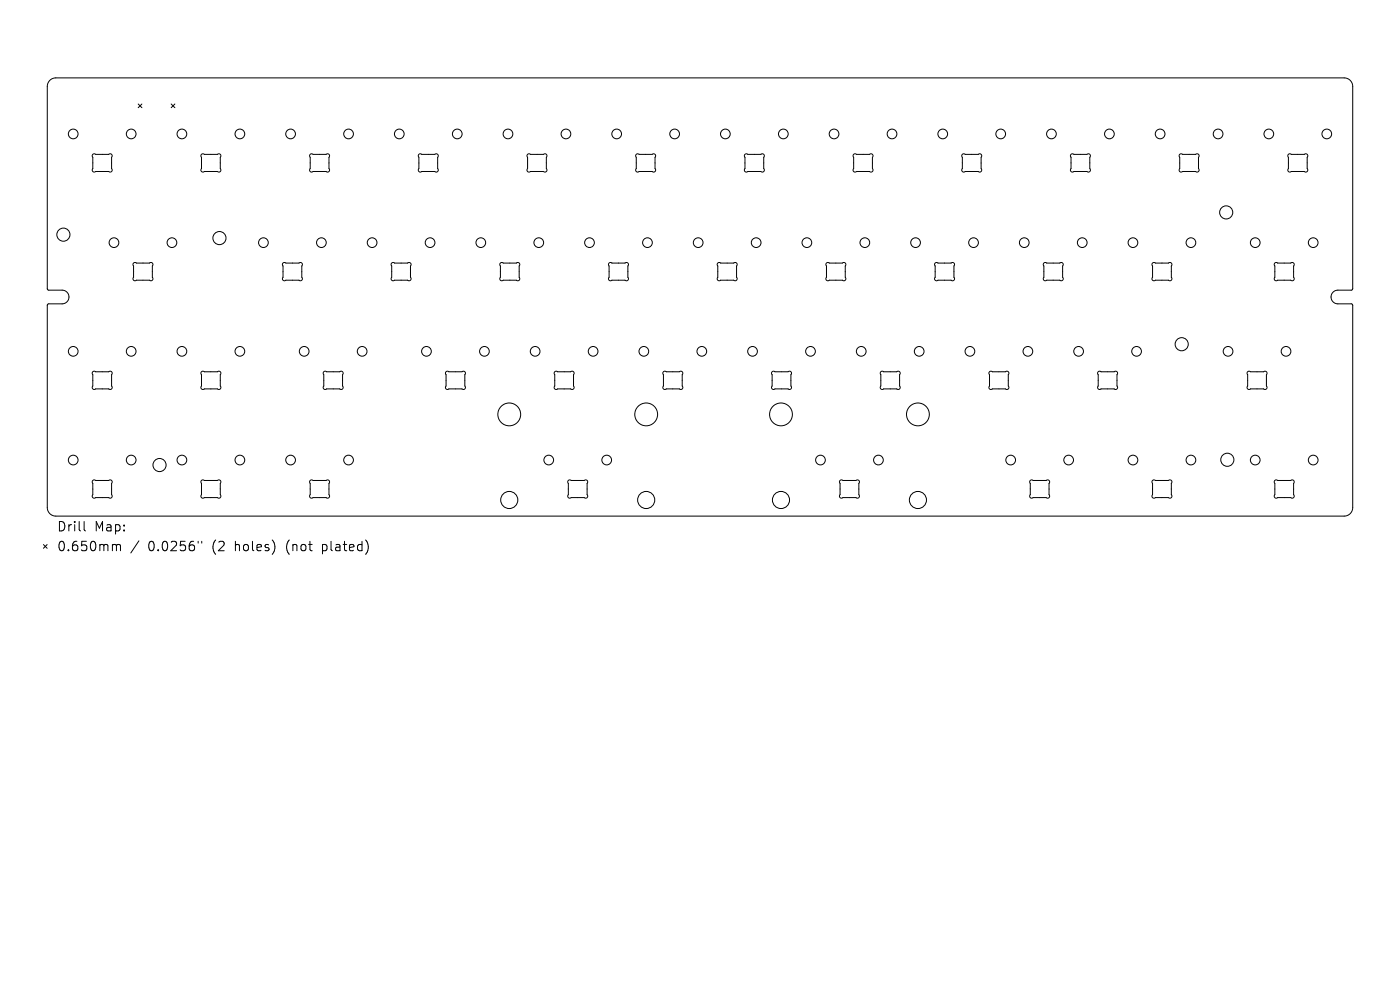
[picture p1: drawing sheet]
<svg xmlns="http://www.w3.org/2000/svg" width="297mm" height="210mm" viewBox="0 0 297 210" stroke-linecap="round" stroke-linejoin="round" font-family="sans-serif">
<defs><g id="words">
<g font-size="2.8">
<text x="12" y="113">Drill</text>
<text x="20" y="113">Map:</text>
<text x="12" y="117.2">0.650mm</text>
<text x="31.4" y="117.2">0.0256&quot;</text>
<text x="45.2" y="117.2">(2</text>
<text x="50.1" y="117.2">holes)</text>
<text x="61.2" y="117.2">(not</text>
<text x="69" y="117.2">plated)</text>
</g>
</g></defs>
<g fill="none" stroke="#000" stroke-width=".21">
<path d="M10.6 17.1l.6-.5 .6-.1h273.4a1.81 1.81 0 0 1 1.8 1.8v43l-.3 .2h-2.9a1.45 1.45 0 0 0-1.4 1.5 1.45 1.45 0 0 0 1.4 1.5h2.9l.3 .2v43a1.81 1.81 0 0 1-1.8 1.8h-273.4a1.82 1.82 0 0 1-1.8-1.8v-43l.3-.2h2.9a1.45 1.45 0 0 0 1.4-1.5 1.45 1.45 0 0 0-1.4-1.5h-2.9l-.3-.2v-43l.2-.7zM19.7 32.7l.3-.1 .3 .1h2.8l.3-.1 .3 .1 .1 .4-.1 .3v3l-.3 .1-.3-.1h-2.8l-.3 .1-.3-.1-.1-.3 .1-.3v-2.4l-.1-.3zM29.3 22.1l.8 .7M30.1 22.1l-.8 .7M36.3 22.1l.8 .7M37.1 22.1l-.8 .7M42.7 32.7l.3-.1 .3 .1h2.8l.3-.1 .3 .1 .2 .4-.2 .3 .1 3-.4 .1-.3-.1h-2.8l-.3 .1-.2-.1-.2-.3 .1-.3v-2.4l-.1-.3zM65.8 32.7l.3-.1 .3 .1h2.8l.3-.1 .3 .1 .1 .4-.1 .3v3l-.3 .1-.3-.1h-2.8l-.3 .1-.3-.1-.1-.3 .1-.3v-2.4l-.1-.3zM88.9 32.7l.3-.1 .3 .1h2.7l.4-.1 .2 .1 .2 .4-.2 .3 .1 3-.4 .1-.3-.1h-2.7l-.3 .1-.3-.1-.2-.3 .2-.3v-2.4l-.2-.3zM111.9 32.7l.3-.1 .3 .1h2.8l.3-.1 .3 .1 .1 .4-.1 .3v3l-.3 .1-.3-.1h-2.8l-.3 .1-.3-.1-.1-.3 .1-.3v-2.4l-.1-.3zM135 32.7l.3-.1 .3 .1h2.8l.3-.1 .2 .1 .2 .4-.1 .3v3l-.3 .1-.3-.1h-2.8l-.3 .1-.3-.1-.2-.3 .2-.3v-2.4l-.2-.3zM158 32.7l.3-.1 .3 .1h2.8l.3-.1 .3 .1 .2 .4-.2 .3 .1 3-.4 .1-.3-.1h-2.8l-.3 .1-.2-.1-.2-.3 .1-.3v-2.4l-.1-.3z"/>
<path d="M181.1 32.7l.3-.1 .3 .1h2.8l.3-.1 .3 .1 .1 .4-.1 .3v3l-.3 .1-.3-.1h-2.8l-.3 .1-.3-.1-.1-.3 .1-.3v-2.4l-.1-.3zM204.1 32.7l.4-.1 .3 .1h2.7l.3-.1 .3 .1 .2 .4-.2 .3 .1 3-.4 .1-.3-.1h-2.7l-.4 .1-.2-.1-.2-.3 .2-.3v-2.4l-.2-.3zM227.2 32.7l.3-.1 .3 .1h2.8l.3-.1 .3 .1 .1 .4-.1 .3v3l-.3 .1-.3-.1h-2.8l-.3 .1-.3-.1-.1-.3 .1-.3v-2.4l-.1-.3zM250.3 32.7l.3-.1 .3 .1h2.8l.3-.1 .2 .1 .2 .3-.1 .4v3l-.3 .1-.3-.1h-2.8l-.3 .1-.3-.1-.2-.3 .2-.3v-2.4l-.2-.3zM273.3 32.7l.3-.1 .3 .1h2.8l.3-.1 .3 .1 .1 .3-.1 .4v3l-.3 .1-.3-.1h-2.8l-.3 .1-.3-.1-.1-.3 .1-.3v-2.4l-.1-.3zM28.3 55.8l.3-.1 .3 .1h2.8l.3-.1 .3 .1 .1 .3-.1 .3v3l-.3 .2-.3-.2h-2.8l-.3 .2-.2-.1-.2-.4 .1-.3v-2.4l-.1-.3zM60 55.8l.3-.1 .3 .1h2.8l.3-.1 .3 .1 .2 .3-.2 .3 .1 3-.4 .2-.3-.2h-2.8l-.3 .2-.2-.1-.2-.4 .1-.3v-2.4l-.1-.3zM83.1 55.8l.3-.1 .3 .1h2.8l.3-.1 .3 .1 .1 .3-.1 .3v3l-.3 .2-.3-.2h-2.8l-.3 .2-.3-.1-.1-.4 .1-.3v-2.4l-.1-.3zM106.2 55.8l.3-.1 .3 .1h2.7l.4-.1 .2 .1 .2 .3-.2 .3 .1 3-.4 .2-.3-.2h-2.7l-.4 .2-.2-.1-.2-.4 .2-.3v-2.4l-.2-.3zM129.2 55.8l.3-.1 .3 .1h2.8l.3-.1 .3 .1 .1 .3-.1 .3v3l-.3 .2-.3-.2h-2.8l-.3 .2-.3-.1-.1-.4 .1-.3v-2.4l-.1-.3zM152.3 55.8l.3-.1 .3 .1h2.8l.3-.1 .2 .1 .2 .3-.1 .3v3l-.3 .2-.3-.2h-2.8l-.3 .2-.3-.1-.2-.4 .2-.3v-2.4l-.2-.3zM175.3 55.8l.3-.1 .3 .1h2.8l.3-.1 .3 .1 .1 .3-.1 .3v3l-.3 .2-.3-.2h-2.8l-.3 .2-.3-.1-.1-.4 .1-.3v-2.4l-.1-.3z"/>
<path d="M198.4 55.8l.3-.1 .3 .1h2.8l.3-.1 .3 .1 .1 .3-.1 .3v3l-.3 .2-.3-.2h-2.8l-.3 .2-.3-.1-.1-.4 .1-.3v-2.4l-.1-.3zM221.4 55.8l.3-.1 .3 .1h2.8l.3-.1 .3 .1 .2 .3-.2 .3 .1 3-.4 .2-.3-.2h-2.8l-.3 .2-.2-.1-.2-.4 .1-.3v-2.4l-.1-.3zM244.5 55.8l.3-.1 .3 .1h2.8l.3-.1 .3 .1 .1 .3-.1 .3v3l-.3 .2-.3-.2h-2.8l-.3 .2-.3-.1-.1-.4 .1-.3v-2.4l-.1-.3zM270.4 55.8l.3-.1 .3 .1h2.8l.3-.1 .3 .1 .2 .3-.2 .3 .1 3-.4 .2-.3-.2h-2.8l-.3 .2-.2-.1-.2-.3 .1-.4v-2.4l-.1-.3zM19.7 78.9l.3-.2 .3 .2h2.8l.3-.2 .3 .1 .1 .4-.1 .3v3l-.3 .1-.3-.1h-2.8l-.3 .1-.3-.1-.1-.3 .1-.3v-2.4l-.1-.3zM42.7 78.9l.3-.2 .3 .2h2.8l.3-.2 .3 .1 .2 .4-.2 .3 .1 3-.4 .1-.3-.1h-2.8l-.3 .1-.2-.1-.2-.3 .1-.3v-2.4l-.1-.3zM68.7 78.9l.3-.2 .3 .2h2.8l.3-.2 .3 .1 .1 .4-.1 .3v3l-.3 .1-.3-.1h-2.8l-.3 .1-.3-.1-.1-.3 .1-.3v-2.4l-.1-.3zM94.6 78.9l.3-.2 .3 .2h2.8l.3-.2 .3 .1 .1 .4-.1 .3v3l-.3 .1-.3-.1h-2.8l-.3 .1-.3-.1-.1-.3 .1-.3v-2.4l-.1-.3zM117.7 78.9l.3-.2 .3 .2h2.8l.3-.2 .3 .1 .1 .4-.1 .3v3l-.3 .1-.3-.1h-2.8l-.3 .1-.3-.1-.1-.3 .1-.3v-2.4l-.1-.3zM140.7 78.9l.3-.2 .3 .2h2.8l.3-.2 .3 .1 .2 .4-.2 .3 .1 3-.4 .1-.3-.1h-2.8l-.3 .1-.2-.1-.2-.3 .1-.3v-2.4l-.1-.3zM163.8 78.9l.3-.2 .3 .2h2.8l.3-.2 .3 .1 .1 .4-.1 .3v3l-.3 .1-.3-.1h-2.8l-.3 .1-.3-.1-.1-.3 .1-.3v-2.4l-.1-.3zM186.9 78.9l.3-.2 .3 .2h2.7l.4-.2 .2 .1 .2 .4-.2 .3 .1 3-.4 .1-.3-.1h-2.7l-.3 .1-.3-.1-.2-.3 .2-.3v-2.4l-.2-.3z"/>
<path d="M209.9 78.9l.3-.2 .3 .2h2.8l.3-.2 .3 .1 .1 .4-.1 .3v3l-.3 .1-.3-.1h-2.8l-.3 .1-.3-.1-.1-.3 .1-.3v-2.4l-.1-.3zM233 78.9l.3-.2 .3 .2h2.8l.3-.2 .2 .1 .2 .4-.1 .3v3l-.3 .1-.3-.1h-2.8l-.3 .1-.3-.1-.2-.3 .2-.3v-2.4l-.2-.3zM264.7 78.9l.3-.2 .3 .2h2.8l.3-.2 .3 .1 .1 .4-.1 .3v3l-.3 .1-.3-.1h-2.8l-.3 .1-.3-.1-.1-.3 .1-.3v-2.4l-.1-.3zM9.2 115.5l.8 .8M10 115.5l-.8 .8M17.8 110.6v1.7l.3 .3M19.7 101.9l.3-.1 .3 .1h2.8l.3-.1 .3 .1 .1 .3-.1 .3v3l-.3 .2-.3-.1h-2.8l-.3 .1-.3-.1-.1-.4 .1-.3v-2.4l-.1-.3zM24.1 115.5l.5 .1 .1 .2M24.7 115.8l.3-.3 .5 .1 .1 1.2M24.7 115.8v1M29.5 114.7l-1.7 2.6M42 114.8v.4"/>
<path d="M42.7 101.9l.3-.1 .3 .1h2.8l.3-.1 .3 .1 .2 .3-.2 .3 .1 3-.4 .2-.3-.1h-2.8l-.3 .1-.2-.1-.2-.4 .1-.3v-2.4l-.1-.3zM42.8 114.8v.4M65.8 101.9l.3-.1 .3 .1h2.8l.3-.1 .3 .1 .1 .3-.1 .3v3l-.3 .2-.3-.1h-2.8l-.3 .1-.3-.1-.1-.4 .1-.3v-2.4l-.1-.3zM120.6 101.9l.3-.1 .3 .1h2.8l.3-.1 .2 .1 .2 .3-.1 .3v3l-.3 .2-.3-.1h-2.8l-.3 .1-.3-.1-.2-.4 .2-.3v-2.4l-.2-.3zM178.2 101.9l.3-.1 .3 .1h2.8l.3-.1 .3 .1 .1 .3-.1 .3v3l-.3 .2-.3-.1h-2.8l-.3 .1-.3-.1-.1-.4 .1-.3v-2.4l-.1-.3zM218.6 101.9l.3-.1 .3 .1h2.8l.3-.1 .2 .1 .2 .3-.2 .3 .1 3-.3 .2-.3-.1h-2.8l-.3 .1-.3-.1-.2-.4 .2-.3v-2.4l-.2-.3zM244.5 101.9l.3-.1 .3 .1h2.8l.3-.1 .3 .1 .1 .3-.1 .3v3l-.3 .2-.3-.1h-2.8l-.3 .1-.3-.1-.1-.4 .1-.3v-2.4l-.1-.3zM270.4 101.9l.3-.1 .3 .1h2.8l.3-.1 .3 .1 .2 .3-.2 .3 .1 3-.4 .2-.3-.1h-2.8l-.3 .1-.2-.1-.2-.3 .1-.4v-2.4l-.1-.3z"/>
<circle cx="15.5" cy="28.4" r="1.03"/>
<circle cx="27.8" cy="28.4" r="1.03"/>
<circle cx="38.6" cy="28.4" r="1.03"/>
<circle cx="50.9" cy="28.4" r="1.03"/>
<circle cx="61.6" cy="28.4" r="1.03"/>
<circle cx="73.9" cy="28.4" r="1.03"/>
<circle cx="84.7" cy="28.4" r="1.03"/>
<circle cx="97" cy="28.4" r="1.03"/>
<circle cx="107.8" cy="28.4" r="1.03"/>
<circle cx="120.1" cy="28.4" r="1.03"/>
<circle cx="130.8" cy="28.4" r="1.03"/>
<circle cx="143.1" cy="28.4" r="1.03"/>
<circle cx="153.9" cy="28.4" r="1.03"/>
<circle cx="166.2" cy="28.4" r="1.03"/>
<circle cx="176.9" cy="28.4" r="1.03"/>
<circle cx="189.2" cy="28.4" r="1.03"/>
<circle cx="200" cy="28.4" r="1.03"/>
<circle cx="212.3" cy="28.4" r="1.03"/>
<circle cx="223.1" cy="28.4" r="1.03"/>
<circle cx="235.4" cy="28.4" r="1.03"/>
<circle cx="246.1" cy="28.4" r="1.03"/>
<circle cx="258.4" cy="28.4" r="1.03"/>
<circle cx="269.2" cy="28.4" r="1.03"/>
<circle cx="281.5" cy="28.4" r="1.03"/>
<circle cx="13.4" cy="49.8" r="1.39"/>
<circle cx="24.2" cy="51.5" r="1.03"/>
<circle cx="36.5" cy="51.5" r="1.03"/>
<circle cx="46.6" cy="50.5" r="1.39"/>
<circle cx="55.9" cy="51.5" r="1.03"/>
<circle cx="68.2" cy="51.5" r="1.03"/>
<circle cx="78.9" cy="51.5" r="1.03"/>
<circle cx="91.2" cy="51.5" r="1.03"/>
<circle cx="102" cy="51.5" r="1.03"/>
<circle cx="114.3" cy="51.5" r="1.03"/>
<circle cx="125.1" cy="51.5" r="1.03"/>
<circle cx="137.4" cy="51.5" r="1.03"/>
<circle cx="148.1" cy="51.5" r="1.03"/>
<circle cx="160.4" cy="51.5" r="1.03"/>
<circle cx="171.2" cy="51.5" r="1.03"/>
<circle cx="183.5" cy="51.5" r="1.03"/>
<circle cx="194.2" cy="51.5" r="1.03"/>
<circle cx="206.5" cy="51.5" r="1.03"/>
<circle cx="217.3" cy="51.5" r="1.03"/>
<circle cx="229.6" cy="51.5" r="1.03"/>
<circle cx="240.3" cy="51.5" r="1.03"/>
<circle cx="252.6" cy="51.5" r="1.03"/>
<circle cx="260.1" cy="45.1" r="1.39"/>
<circle cx="266.3" cy="51.5" r="1.03"/>
<circle cx="278.6" cy="51.5" r="1.03"/>
<circle cx="15.5" cy="74.5" r="1.03"/>
<circle cx="27.8" cy="74.5" r="1.03"/>
<circle cx="38.6" cy="74.5" r="1.03"/>
<circle cx="50.9" cy="74.5" r="1.03"/>
<circle cx="64.5" cy="74.5" r="1.03"/>
<circle cx="76.8" cy="74.5" r="1.03"/>
<circle cx="90.5" cy="74.5" r="1.03"/>
<circle cx="102.8" cy="74.5" r="1.03"/>
<circle cx="113.5" cy="74.5" r="1.03"/>
<circle cx="125.8" cy="74.5" r="1.03"/>
<circle cx="136.6" cy="74.5" r="1.03"/>
<circle cx="148.9" cy="74.5" r="1.03"/>
<circle cx="159.6" cy="74.5" r="1.03"/>
<circle cx="171.9" cy="74.5" r="1.03"/>
<circle cx="182.7" cy="74.5" r="1.03"/>
<circle cx="195" cy="74.5" r="1.03"/>
<circle cx="205.8" cy="74.5" r="1.03"/>
<circle cx="218.1" cy="74.5" r="1.03"/>
<circle cx="228.8" cy="74.5" r="1.03"/>
<circle cx="241.1" cy="74.5" r="1.03"/>
<circle cx="250.7" cy="73" r="1.39"/>
<circle cx="260.5" cy="74.5" r="1.03"/>
<circle cx="272.8" cy="74.5" r="1.03"/>
<circle cx="15.5" cy="97.6" r="1.03"/>
<circle cx="27.8" cy="97.6" r="1.03"/>
<circle cx="33.8" cy="98.6" r="1.39"/>
<circle cx="38.6" cy="97.6" r="1.03"/>
<circle cx="50.9" cy="97.6" r="1.03"/>
<circle cx="61.6" cy="97.6" r="1.03"/>
<circle cx="73.9" cy="97.6" r="1.03"/>
<circle cx="108" cy="87.9" r="2.42"/>
<circle cx="116.4" cy="97.6" r="1.03"/>
<circle cx="128.7" cy="97.6" r="1.03"/>
<circle cx="137.1" cy="87.9" r="2.42"/>
<circle cx="165.7" cy="87.9" r="2.42"/>
<circle cx="174.1" cy="97.6" r="1.03"/>
<circle cx="186.4" cy="97.6" r="1.03"/>
<circle cx="194.7" cy="87.9" r="2.42"/>
<circle cx="214.4" cy="97.6" r="1.03"/>
<circle cx="226.7" cy="97.6" r="1.03"/>
<circle cx="240.3" cy="97.6" r="1.03"/>
<circle cx="252.6" cy="97.6" r="1.03"/>
<circle cx="260.4" cy="97.5" r="1.39"/>
<circle cx="266.3" cy="97.6" r="1.03"/>
<circle cx="278.6" cy="97.6" r="1.03"/>
<circle cx="108" cy="106.1" r="1.82"/>
<circle cx="137.1" cy="106.1" r="1.82"/>
<circle cx="165.7" cy="106.1" r="1.82"/>
<circle cx="194.7" cy="106.1" r="1.82"/>
</g>
<use href="#words"/>
</svg>
